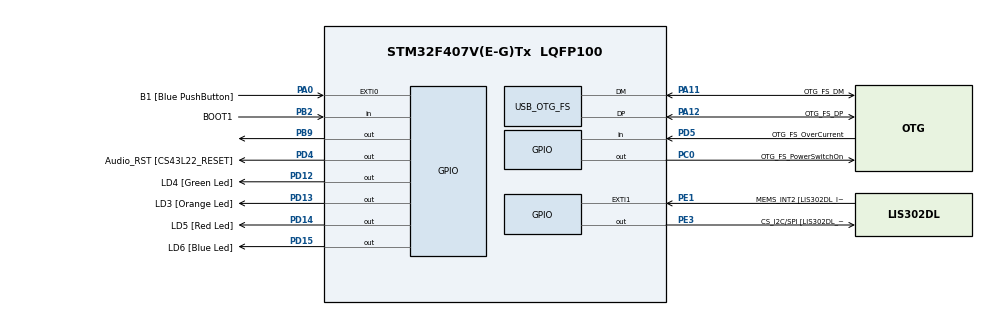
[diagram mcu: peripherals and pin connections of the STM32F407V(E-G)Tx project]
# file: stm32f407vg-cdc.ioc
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Mcu.Family=STM32F4
Mcu.Name=STM32F407V(E-G)Tx
Mcu.Package=LQFP100
NVIC.OTG_FS_IRQn=true\:0\:0\:false\:false\:true
NVIC.PriorityGroup=NVIC_PRIORITYGROUP_0
PA0-WKUP.GPIO_Label=B1 [Blue PushButton]
PA0-WKUP.Signal=GPXTI0
PA10.GPIO_Label=OTG_FS_ID
PA10.GPIO_Mode=GPIO_MODE_AF_PP
PA10.GPIO_PuPd=GPIO_NOPULL
PA10.GPIO_Speed=GPIO_SPEED_FREQ_LOW
PA10.Signal=USB_OTG_FS_ID
PA11.GPIO_Label=OTG_FS_DM
PA11.GPIO_Mode=GPIO_MODE_AF_PP
PA11.GPIO_PuPd=GPIO_NOPULL
PA11.GPIO_Speed=GPIO_SPEED_FREQ_LOW
PA11.Mode=Device_Only
PA11.Signal=USB_OTG_FS_DM
PA12.GPIO_Label=OTG_FS_DP
PA12.GPIO_Mode=GPIO_MODE_AF_PP
PA12.GPIO_PuPd=GPIO_NOPULL
PA12.GPIO_Speed=GPIO_SPEED_FREQ_LOW
PA12.Mode=Device_Only
PA12.Signal=USB_OTG_FS_DP
PA13.GPIO_Label=SWDIO
PA13.Signal=SYS_JTMS-SWDIO
PA14.GPIO_Label=SWCLK
PA14.Signal=SYS_JTCK-SWCLK
PA4.GPIO_Label=I2S3_WS [CS43L22_LRCK]
PA4.GPIO_Mode=GPIO_MODE_AF_PP
PA4.GPIO_PuPd=GPIO_NOPULL
PA4.GPIO_Speed=GPIO_SPEED_FREQ_LOW
PA4.Signal=I2S3_WS
PA5.GPIO_Label=SPI1_SCK [LIS302DL_SCL/SPC]
PA5.GPIO_Mode=GPIO_MODE_AF_PP
PA5.GPIO_PuPd=GPIO_NOPULL
PA5.GPIO_Speed=GPIO_SPEED_FREQ_LOW
PA5.Signal=SPI1_SCK
PA6.GPIO_Label=SPI1_MISO [LIS302DL_SDO]
PA6.GPIO_Mode=GPIO_MODE_AF_PP
PA6.GPIO_PuPd=GPIO_NOPULL
PA6.GPIO_Speed=GPIO_SPEED_FREQ_LOW
PA6.Signal=SPI1_MISO
PA7.GPIO_Label=SPI1_MOSI [LIS302DL_SDA/SDI/SDO]
PA7.GPIO_Mode=GPIO_MODE_AF_PP
PA7.GPIO_PuPd=GPIO_NOPULL
PA7.GPIO_Speed=GPIO_SPEED_FREQ_LOW
PA7.Signal=SPI1_MOSI
PA9.GPIO_Label=VBUS_FS
PA9.GPIO_Mode=GPIO_MODE_INPUT
PA9.GPIO_PuPd=GPIO_NOPULL
PA9.Signal=USB_OTG_FS_VBUS
PB10.GPIO_Label=CLK_IN [MP45DT02_CLK]
PB10.GPIO_Mode=GPIO_MODE_AF_PP
PB10.GPIO_PuPd=GPIO_NOPULL
PB10.GPIO_Speed=GPIO_SPEED_FREQ_LOW
PB10.Signal=I2S2_CK
PB2.GPIO_Label=BOOT1
PB2.GPIO_Mode=GPIO_MODE_INPUT
PB2.GPIO_PuPd=GPIO_NOPULL
PB2.Signal=GPIO_Input
PB3.GPIO_Label=SWO
PB3.Signal=SYS_JTDO-SWO
PB6.GPIO_Label=Audio_SCL [CS43L22_SCL]
PB6.GPIO_Mode=GPIO_MODE_AF_OD
PB6.GPIO_PuPd=GPIO_NOPULL
PB6.GPIO_Speed=GPIO_SPEED_FREQ_LOW
PB6.Signal=I2C1_SCL
PB9.Signal=GPIO_Output
PC0.GPIO_Label=OTG_FS_PowerSwitchOn
PC0.GPIO_PuPd=GPIO_NOPULL
PC0.GPIO_Speed=GPIO_SPEED_FREQ_LOW
PC0.PinState=GPIO_PIN_SET
PC0.Signal=GPIO_Output
PC10.GPIO_Label=I2S3_SCK [CS43L22_SCLK]
PC10.GPIO_Mode=GPIO_MODE_AF_PP
PC10.GPIO_PuPd=GPIO_NOPULL
PC10.GPIO_Speed=GPIO_SPEED_FREQ_LOW
PC10.Signal=I2S3_CK
PC12.GPIO_Label=I2S3_SD [CS43L22_SDIN]
PC12.GPIO_Mode=GPIO_MODE_AF_PP
PC12.GPIO_PuPd=GPIO_NOPULL
PC12.GPIO_Speed=GPIO_SPEED_FREQ_LOW
PC12.Signal=I2S3_SD
PC14-OSC32_IN.GPIO_Label=PC14-OSC32_IN
PC14-OSC32_IN.Signal=RCC_OSC32_IN
PC15-OSC32_OUT.GPIO_Label=PC15-OSC32_OUT
PC15-OSC32_OUT.Signal=RCC_OSC32_OUT
PC3.GPIO_Label=PDM_OUT [MP45DT02_DOUT]
PC3.GPIO_Mode=GPIO_MODE_AF_PP
PC3.GPIO_PuPd=GPIO_NOPULL
PC3.GPIO_Speed=GPIO_SPEED_FREQ_LOW
PC3.Signal=I2S2_SD
PC7.GPIO_Label=I2S3_MCK [CS43L22_MCLK]
PC7.GPIO_Mode=GPIO_MODE_AF_PP
PC7.GPIO_PuPd=GPIO_NOPULL
PC7.GPIO_Speed=GPIO_SPEED_FREQ_LOW
PC7.Signal=I2S3_MCK
PD12.GPIO_Label=LD4 [Green Led]
PD12.GPIO_PuPd=GPIO_NOPULL
PD12.GPIO_Speed=GPIO_SPEED_FREQ_LOW
PD12.Signal=GPIO_Output
PD13.GPIO_Label=LD3 [Orange Led]
PD13.GPIO_PuPd=GPIO_NOPULL
PD13.GPIO_Speed=GPIO_SPEED_FREQ_LOW
PD13.Signal=GPIO_Output
PD14.GPIO_Label=LD5 [Red Led]
PD14.GPIO_PuPd=GPIO_NOPULL
PD14.GPIO_Speed=GPIO_SPEED_FREQ_LOW
PD14.Signal=GPIO_Output
PD15.GPIO_Label=LD6 [Blue Led]
PD15.GPIO_PuPd=GPIO_NOPULL
PD15.GPIO_Speed=GPIO_SPEED_FREQ_LOW
PD15.Signal=GPIO_Output
PD4.GPIO_Label=Audio_RST [CS43L22_RESET]
PD4.GPIO_PuPd=GPIO_NOPULL
PD4.GPIO_Speed=GPIO_SPEED_FREQ_LOW
PD4.Signal=GPIO_Output
PD5.GPIO_Label=OTG_FS_OverCurrent
PD5.GPIO_Mode=GPIO_MODE_INPUT
PD5.GPIO_PuPd=GPIO_NOPULL
PD5.Signal=GPIO_Input
PE1.GPIO_Label=MEMS_INT2 [LIS302DL_INT2]
PE1.GPIO_ModeDefaultEXTI=GPIO_MODE_EVT_RISING
PE1.GPIO_PuPd=GPIO_NOPULL
PE1.Signal=GPXTI1
PE3.GPIO_Label=CS_I2C/SPI [LIS302DL_CS_I2C/SPI]
PE3.GPIO_PuPd=GPIO_NOPULL
PE3.GPIO_Speed=GPIO_SPEED_FREQ_LOW
PE3.Signal=GPIO_Output
PH0-OSC_IN.GPIO_Label=PH0-OSC_IN
PH0-OSC_IN.Mode=HSE-External-Oscillator
PH0-OSC_IN.Signal=RCC_OSC_IN
PH1-OSC_OUT.GPIO_Label=PH1-OSC_OUT
PH1-OSC_OUT.Mode=HSE-External-Oscillator
PH1-OSC_OUT.Signal=RCC_OSC_OUT
ProjectManager.HeapSize=0x200
ProjectManager.StackSize=0x400
ProjectManager.TargetToolchain=EWARM
RCC.48MHZClocksFreq_Value=48000000
RCC.AHBFreq_Value=168000000
RCC.APB1CLKDivider=RCC_HCLK_DIV4
RCC.APB1Freq_Value=42000000
RCC.APB1TimFreq_Value=84000000
RCC.APB2CLKDivider=RCC_HCLK_DIV2
RCC.APB2Freq_Value=84000000
RCC.APB2TimFreq_Value=168000000
RCC.CortexFreq_Value=168000000
RCC.HCLKFreq_Value=168000000
RCC.HSE_VALUE=8000000
RCC.HSI_VALUE=16000000
RCC.LSE_VALUE=32768
RCC.PLLM=8
RCC.PLLN=336
RCC.PLLQ=7
RCC.SYSCLKFreq_VALUE=168000000
RCC.SYSCLKSource=RCC_SYSCLKSOURCE_PLLCLK
RCC.VCOOutputFreq_Value=336000000
USB_DEVICE.CLASS_NAME-CDC_FS=CDC
USB_DEVICE.CLASS_NAME_FS=CDC
USB_DEVICE.USBD_CDC_INTERVAL-CDC_FS=5
USB_DEVICE.USBD_HandleTypeDef-CDC_FS=hUsbDeviceFS
USB_DEVICE.VirtualMode-CDC_FS=Cdc
USB_DEVICE.VirtualModeFS=Cdc_FS
USB_OTG_FS.VirtualMode=Device_Only
USB_OTG_FS.vbus_sensing_enable=DISABLE
VP_USB_DEVICE_VS_USB_DEVICE_CDC_FS.Mode=CDC_FS
board=STM32F407G-DISC1

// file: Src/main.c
/**
  ******************************************************************************
  * File Name          : main.c
  * Description        : Main program body
  ******************************************************************************
  *
  * Copyright (c) 2016 STMicroelectronics International N.V.
  * All rights reserved.
  *
  * Redistribution and use in source and binary forms, with or without
  * modification, are permitted, provided that the following conditions are met:
  *
  * 1. Redistribution of source code must retain the above copyright notice,
  *    this list of conditions and the following disclaimer.
  * 2. Redistributions in binary form must reproduce the above copyright notice,
  *    this list of conditions and the following disclaimer in the documentation
  *    and/or other materials provided with the distribution.
  * 3. Neither the name of STMicroelectronics nor the names of other
  *    contributors to this software may be used to endorse or promote products
  *    derived from this software without specific written permission.
  * 4. This software, including modifications and/or derivative works of this
  *    software, must execute solely and exclusively on microcontroller or
  *    microprocessor devices manufactured by or for STMicroelectronics.
  * 5. Redistribution and use of this software other than as permitted under
  *    this license is void and will automatically terminate your rights under
  *    this license.
  *
  * THIS SOFTWARE IS PROVIDED BY STMICROELECTRONICS AND CONTRIBUTORS "AS IS"
  * AND ANY EXPRESS, IMPLIED OR STATUTORY WARRANTIES, INCLUDING, BUT NOT
  * LIMITED TO, THE IMPLIED WARRANTIES OF MERCHANTABILITY, FITNESS FOR A
  * PARTICULAR PURPOSE AND NON-INFRINGEMENT OF THIRD PARTY INTELLECTUAL PROPERTY
  * RIGHTS ARE DISCLAIMED TO THE FULLEST EXTENT PERMITTED BY LAW. IN NO EVENT
  * SHALL STMICROELECTRONICS OR CONTRIBUTORS BE LIABLE FOR ANY DIRECT, INDIRECT,
  * INCIDENTAL, SPECIAL, EXEMPLARY, OR CONSEQUENTIAL DAMAGES (INCLUDING, BUT NOT
  * LIMITED TO, PROCUREMENT OF SUBSTITUTE GOODS OR SERVICES; LOSS OF USE, DATA,
  * OR PROFITS; OR BUSINESS INTERRUPTION) HOWEVER CAUSED AND ON ANY THEORY OF
  * LIABILITY, WHETHER IN CONTRACT, STRICT LIABILITY, OR TORT (INCLUDING
  * NEGLIGENCE OR OTHERWISE) ARISING IN ANY WAY OUT OF THE USE OF THIS SOFTWARE,
  * EVEN IF ADVISED OF THE POSSIBILITY OF SUCH DAMAGE.
  *
  ******************************************************************************
  */
#include "main.h"
#include "stm32f4xx_hal.h"
#include "usb_device.h"
#include "usbd_cdc_if.h"
#include "sc.h"
#include "i2c.h"
#include "common.h"
#include "gpio.h"

/* USER CODE BEGIN Includes */
#define STM32_VCP_BASE                  0x00
#define STM32_VCP_GPIO_BASE             0x10
#define STM32_VCP_SC_BASE               0x20
#define STM32_VCP_ADC_BASE              0x30
#define STM32_VCP_OWCI_BASE             0x40
#define STM32_VCP_I2C_BASE              0x50
#define STM32_VCP_SPI_BASE              0x60

/* USER CODE END Includes */

/* USER CODE BEGIN PV */
/* Private variables ---------------------------------------------------------*/
extern uint8_t UserRxBufferFS[APP_RX_DATA_SIZE];
extern uint8_t UserTxBufferFS[APP_TX_DATA_SIZE];
extern volatile int8_t rxIndicator;
/* USER CODE END PV */

void SystemClock_Config(void);
void Error_Handler(void);
static void MX_GPIO_Init(void);

/* USER CODE BEGIN PFP */
/* Private function prototypes -----------------------------------------------*/
void stm32_Vcp_Base_Process(uint8_t* pCommand);

/* USER CODE END PFP */

int main(void)
{

  /* MCU Configuration----------------------------------------------------------*/

  /* Reset of all peripherals, Initializes the Flash interface and the Systick. */
  HAL_Init();

  /* Configure the system clock */
  SystemClock_Config();

  /* Initialize all configured peripherals */
  MX_GPIO_Init();
  MX_USB_DEVICE_Init();

  /* Infinite loop */
  while (1)
  {
    if( rxIndicator == 0x55)
    {
      rxIndicator = 0x00;

      if(UserRxBufferFS[0] == 0x5A )
      {
        switch (UserRxBufferFS[1])
        {
          case STM32_VCP_BASE:
            stm32_Vcp_Base_Process(UserRxBufferFS);
            break;

          case STM32_VCP_GPIO_BASE:
            stm32_Vcp_Gpio_Process(UserRxBufferFS);
            break;

          case STM32_VCP_SC_BASE:
            stm32_Vcp_Sc_Process(UserRxBufferFS);
            break;

          case STM32_VCP_ADC_BASE:
//            stm32_Vcp_Adc_Process(UserRxBufferFS);
            break;

          case STM32_VCP_OWCI_BASE:
//            stm32_Vcp_Owci_Process(UserRxBufferFS);
            break;

          case STM32_VCP_I2C_BASE:
//            stm32_Vcp_I2c_Process(UserRxBufferFS);
            break;

          case STM32_VCP_SPI_BASE:
//            stm32_Vcp_SPI_Process(UserRxBufferFS);
            break;

          default:
            break;
        }

      }
    }

  }

}

/** System Clock Configuration
*/
void SystemClock_Config(void)
{

  RCC_OscInitTypeDef RCC_OscInitStruct;
  RCC_ClkInitTypeDef RCC_ClkInitStruct;

    /**Configure the main internal regulator output voltage
    */
  __HAL_RCC_PWR_CLK_ENABLE();

  __HAL_PWR_VOLTAGESCALING_CONFIG(PWR_REGULATOR_VOLTAGE_SCALE1);

    /**Initializes the CPU, AHB and APB busses clocks
    */
  RCC_OscInitStruct.OscillatorType = RCC_OSCILLATORTYPE_HSE;
  RCC_OscInitStruct.HSEState = RCC_HSE_ON;
  RCC_OscInitStruct.PLL.PLLState = RCC_PLL_ON;
  RCC_OscInitStruct.PLL.PLLSource = RCC_PLLSOURCE_HSE;
  RCC_OscInitStruct.PLL.PLLM = 25;
  RCC_OscInitStruct.PLL.PLLN = 336;
  RCC_OscInitStruct.PLL.PLLP = RCC_PLLP_DIV2;
  RCC_OscInitStruct.PLL.PLLQ = 7;
  if (HAL_RCC_OscConfig(&RCC_OscInitStruct) != HAL_OK)
  {
    Error_Handler();
  }

    /**Initializes the CPU, AHB and APB busses clocks
    */
  RCC_ClkInitStruct.ClockType = RCC_CLOCKTYPE_HCLK|RCC_CLOCKTYPE_SYSCLK
                              |RCC_CLOCKTYPE_PCLK1|RCC_CLOCKTYPE_PCLK2;
  RCC_ClkInitStruct.SYSCLKSource = RCC_SYSCLKSOURCE_PLLCLK;
  RCC_ClkInitStruct.AHBCLKDivider = RCC_SYSCLK_DIV1;
  RCC_ClkInitStruct.APB1CLKDivider = RCC_HCLK_DIV4;
  RCC_ClkInitStruct.APB2CLKDivider = RCC_HCLK_DIV2;

  if (HAL_RCC_ClockConfig(&RCC_ClkInitStruct, FLASH_LATENCY_5) != HAL_OK)
  {
    Error_Handler();
  }

    /**Configure the Systick interrupt time
    */
  HAL_SYSTICK_Config(HAL_RCC_GetHCLKFreq()/1000);

    /**Configure the Systick
    */
  HAL_SYSTICK_CLKSourceConfig(SYSTICK_CLKSOURCE_HCLK);

  /* SysTick_IRQn interrupt configuration */
  HAL_NVIC_SetPriority(SysTick_IRQn, 0, 0);
}

/** Configure pins as
        * Analog
        * Input
        * Output
        * EVENT_OUT
        * EXTI
     PC0   ------> USR_IO_0
     PC1   ------> USR_IO_1
     PC2   ------> USR_IO_2
     PC3   ------> USR_IO_3
     PC4   ------> USR_IO_4
     PC5   ------> USR_IO_5

     PA0   ------> ADC IN0
     PA1   ------> ADC IN1
     PA2   ------> ADC IN2
     PA3   ------> ADC IN3
     PA4   ------> ADC IN4
     PA5   ------> ADC IN5
     PA6   ------> ADC IN6
     PA7   ------> ADC IN

     PF0   ------> I2C_SCL
     PF1   ------> I2C_SDA

     PB9   ------> LED on VE board

     PB13   ------> SC_SCK
     PB15   ------> SC_DATA

*/
static void MX_GPIO_Init(void)
{

  GPIO_InitTypeDef GPIO_InitStruct;

  /* GPIO Ports Clock Enable */
  __HAL_RCC_GPIOE_CLK_ENABLE();
  __HAL_RCC_GPIOC_CLK_ENABLE();
  __HAL_RCC_GPIOH_CLK_ENABLE();
  __HAL_RCC_GPIOA_CLK_ENABLE();
  __HAL_RCC_GPIOB_CLK_ENABLE();
  __HAL_RCC_GPIOD_CLK_ENABLE();

  /*Configure GPIO pin Output Level */
  HAL_GPIO_WritePin(USR_IO_A_Port, USR_IO_A_0 | USR_IO_A_1 | USR_IO_A_2 | USR_IO_A_3 | USR_IO_A_4 | USR_IO_A_5, GPIO_PIN_RESET);
  HAL_GPIO_WritePin(OTG_FS_PowerSwitchOn_GPIO_Port, OTG_FS_PowerSwitchOn_Pin, GPIO_PIN_SET);
  HAL_GPIO_WritePin(GPIOD, LD4_Pin|LD3_Pin|LD5_Pin|LD6_Pin, GPIO_PIN_RESET);
  HAL_GPIO_WritePin(GPIOB, GPIO_PIN_9, GPIO_PIN_RESET);

  /*Configure GPIO pin : USR_IO Group A */
  GPIO_InitStruct.Pin = USR_IO_A_0 | USR_IO_A_1 | USR_IO_A_2 | USR_IO_A_3 | USR_IO_A_4 | USR_IO_A_5;
  GPIO_InitStruct.Mode = GPIO_MODE_OUTPUT_PP;
  GPIO_InitStruct.Pull = GPIO_NOPULL;
  GPIO_InitStruct.Speed = GPIO_SPEED_FREQ_LOW;
  HAL_GPIO_Init(USR_IO_A_Port, &GPIO_InitStruct);

  /*Configure GPIO pin : OTG_FS_PowerSwitchOn_Pin */
  GPIO_InitStruct.Pin = OTG_FS_PowerSwitchOn_Pin;
  GPIO_InitStruct.Mode = GPIO_MODE_OUTPUT_PP;
  GPIO_InitStruct.Pull = GPIO_NOPULL;
  GPIO_InitStruct.Speed = GPIO_SPEED_FREQ_LOW;
  HAL_GPIO_Init(OTG_FS_PowerSwitchOn_GPIO_Port, &GPIO_InitStruct);

  /*Configure GPIO pin : B1_Pin */
  GPIO_InitStruct.Pin = B1_Pin;
  GPIO_InitStruct.Mode = GPIO_MODE_IT_RISING;
  GPIO_InitStruct.Pull = GPIO_NOPULL;
  HAL_GPIO_Init(B1_GPIO_Port, &GPIO_InitStruct);

  /*Configure GPIO pin : BOOT1_Pin */
  GPIO_InitStruct.Pin = BOOT1_Pin;
  GPIO_InitStruct.Mode = GPIO_MODE_INPUT;
  GPIO_InitStruct.Pull = GPIO_NOPULL;
  HAL_GPIO_Init(BOOT1_GPIO_Port, &GPIO_InitStruct);

  /*Configure GPIO pins : LD4_Pin LD3_Pin LD5_Pin LD6_Pin */
  GPIO_InitStruct.Pin = LD4_Pin|LD3_Pin|LD5_Pin|LD6_Pin;
  GPIO_InitStruct.Mode = GPIO_MODE_OUTPUT_PP;
  GPIO_InitStruct.Pull = GPIO_NOPULL;
  GPIO_InitStruct.Speed = GPIO_SPEED_FREQ_LOW;
  HAL_GPIO_Init(GPIOD, &GPIO_InitStruct);

  /*Configure GPIO pin : OTG_FS_OverCurrent_Pin */
  GPIO_InitStruct.Pin = OTG_FS_OverCurrent_Pin;
  GPIO_InitStruct.Mode = GPIO_MODE_INPUT;
  GPIO_InitStruct.Pull = GPIO_NOPULL;
  HAL_GPIO_Init(OTG_FS_OverCurrent_GPIO_Port, &GPIO_InitStruct);

  /*Configure GPIO pin : PB9 */
  GPIO_InitStruct.Pin = GPIO_PIN_9 | GPIO_PIN_13 | GPIO_PIN_15 | GPIO_PIN_3 | GPIO_PIN_5 | GPIO_PIN_7  | GPIO_PIN_6;
  GPIO_InitStruct.Mode = GPIO_MODE_OUTPUT_PP;
  GPIO_InitStruct.Pull = GPIO_NOPULL;
  GPIO_InitStruct.Speed = GPIO_SPEED_FREQ_LOW;
  HAL_GPIO_Init(GPIOB, &GPIO_InitStruct);

  /*Configure GPIO pin : SCL and SDA */
  GPIO_InitStruct.Pin = GPIO_PIN_12 | GPIO_PIN_14;
  GPIO_InitStruct.Mode = GPIO_MODE_OUTPUT_OD;
  GPIO_InitStruct.Pull = GPIO_NOPULL;
  GPIO_InitStruct.Speed = GPIO_SPEED_FREQ_LOW;
  HAL_GPIO_Init(GPIOB, &GPIO_InitStruct);

}

/* USER CODE BEGIN 4 */
void stm32_Vcp_Base_Process(uint8_t* pCommand)
{

}

/* USER CODE END 4 */

void Error_Handler(void)
{
  while(1)
  {
  }
}

/************************ (C) COPYRIGHT STMicroelectronics *****END OF FILE****/
